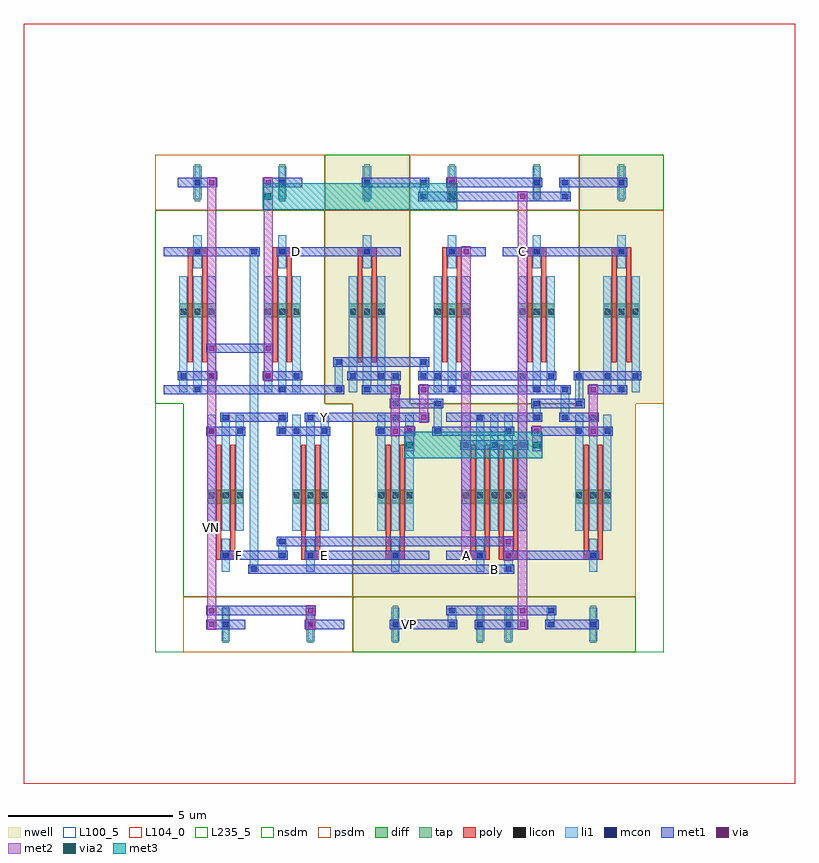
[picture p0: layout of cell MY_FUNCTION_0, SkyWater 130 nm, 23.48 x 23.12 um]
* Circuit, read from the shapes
.subckt MY_FUNCTION_0 A B C D E F VN VP Y
XM1 n1 B VN VN sky130_fd_pr__nfet_01v8 w=0.42 l=0.15 m=2
XM2 n2 F VN VN sky130_fd_pr__nfet_01v8 w=0.42 l=0.15 m=2
XM3 n1 D VN VN sky130_fd_pr__nfet_01v8 w=0.42 l=0.15 m=2
XM4 Y E n2 VN sky130_fd_pr__nfet_01v8 w=0.42 l=0.15 m=2
XM5 Y A n1 VN sky130_fd_pr__nfet_01v8 w=0.42 l=0.15 m=2
XM6 Y C n1 VN sky130_fd_pr__nfet_01v8 w=0.42 l=0.15 m=2
XM7 n3 D n4 VP sky130_fd_pr__pfet_01v8 w=0.42 l=0.15 m=2
XM8 Y E n3 VP sky130_fd_pr__pfet_01v8 w=0.42 l=0.15 m=2
XM9 n5 A VP VP sky130_fd_pr__pfet_01v8 w=0.42 l=0.15 m=2
XM10 n4 B VP VP sky130_fd_pr__pfet_01v8 w=0.42 l=0.15 m=2
XM11 Y F n3 VP sky130_fd_pr__pfet_01v8 w=0.42 l=0.15 m=2
XM12 n3 C n5 VP sky130_fd_pr__pfet_01v8 w=0.42 l=0.15 m=2
.ends

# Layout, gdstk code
from math import pi, radians
import gdstk
lib = gdstk.Library(unit=1e-6, precision=1e-09)
def R(c, l, rs):  # rectangles x0, y0, x1, y1
    for r in rs: c.add(gdstk.rectangle(r[:2], r[2:], *l))
def A(c, l, x, y, w, h, nx, ny, dx, dy):  # array of equal rectangles
    R(c, l, [(x+i*dx, y+j*dy, x+i*dx+w, y+j*dy+h) for i in range(nx) for j in range(ny)])
def P(c, l, *ps):  # polygons
    for p in ps: c.add(gdstk.Polygon(p, *l))
nwell = (64, 20)
diff = (65, 20)
tap = (65, 44)
poly = (66, 20)
licon = (66, 44)
li1 = (67, 20)
mcon = (67, 44)
met1 = (68, 20)
via = (68, 44)
met2 = (69, 20)
via2 = (69, 44)
met3 = (70, 20)
nsdm = (93, 44)
psdm = (94, 20)
L100_5 = (100, 5)
L104_0 = (104, 0)
L235_5 = (235, 5)

dp_pmos_47381084_x1_y1_1 = lib.new_cell('DP_PMOS_47381084_X1_Y1_1676456966')
R(dp_pmos_47381084_x1_y1_1, nwell, [(0,0,3.44,7.56)])
R(dp_pmos_47381084_x1_y1_1, diff, [(0.735,2.625,2.705,3.045)])
R(dp_pmos_47381084_x1_y1_1, tap, [(1.205,6.16,1.375,7.28), (2.065,6.16,2.235,7.28)])
A(dp_pmos_47381084_x1_y1_1, poly, 1, 1.26, 0.15, 3.36, 4, 1, 0.43, 0)
R(dp_pmos_47381084_x1_y1_1, poly, [(1,4.485,1.58,4.755), (1.86,4.485,2.44,4.755)])
A(dp_pmos_47381084_x1_y1_1, licon, 0.775, 2.705, 0.17, 0.17, 3, 1, 0.43, 0)
A(dp_pmos_47381084_x1_y1_1, licon, 1.635, 2.705, 0.17, 0.17, 3, 1, 0.43, 0)
R(dp_pmos_47381084_x1_y1_1, licon, [(1.205,4.535,1.375,4.705), (2.065,4.535,2.235,4.705), (1.205,6.635,1.375,6.805), (2.065,6.635,2.235,6.805)])
A(dp_pmos_47381084_x1_y1_1, li1, 0.735, 0.335, 0.25, 3.53, 5, 1, 0.43, 0)
R(dp_pmos_47381084_x1_y1_1, li1, [(1.165,4.115,1.415,5.125), (2.025,4.115,2.275,5.125), (1.165,6.215,1.415,7.225), (2.025,6.215,2.275,7.225)])
A(dp_pmos_47381084_x1_y1_1, mcon, 0.775, 1.175, 0.17, 0.17, 3, 1, 0.86, 0)
R(dp_pmos_47381084_x1_y1_1, mcon, [(1.205,0.335,1.375,0.505), (2.065,0.755,2.235,0.925), (1.205,4.535,1.375,4.705), (2.065,4.955,2.235,5.125), (1.205,6.635,1.375,6.805), (2.065,6.635,2.235,6.805)])
R(dp_pmos_47381084_x1_y1_1, met1, [(0.26,0.28,1.46,0.56), (1.12,0.7,2.32,0.98), (0.69,1.12,2.75,1.4), (0.26,4.48,1.46,4.76), (1.12,4.9,2.32,5.18), (1.12,6.58,2.75,6.86)])
R(dp_pmos_47381084_x1_y1_1, via, [(2.505,1.185,2.655,1.335), (2.505,6.645,2.655,6.795)])
R(dp_pmos_47381084_x1_y1_1, met2, [(2.44,1.1,2.72,6.88)])
R(dp_pmos_47381084_x1_y1_1, nsdm, [(0,5.88,3.44,7.56)])
R(dp_pmos_47381084_x1_y1_1, psdm, [(0,0,3.44,5.88)])
R(dp_pmos_47381084_x1_y1_1, L100_5, [(0,0,3.44,7.56)])

nmos_s_81537667_x1_y1_16 = lib.new_cell('NMOS_S_81537667_X1_Y1_1676456968')
R(nmos_s_81537667_x1_y1_16, diff, [(0.735,2.625,1.845,3.045)])
R(nmos_s_81537667_x1_y1_16, tap, [(1.205,6.16,1.375,7.28)])
R(nmos_s_81537667_x1_y1_16, poly, [(1,1.26,1.15,4.62), (1.43,1.26,1.58,4.62), (1,4.485,1.58,4.755)])
A(nmos_s_81537667_x1_y1_16, licon, 0.775, 2.705, 0.17, 0.17, 3, 1, 0.43, 0)
R(nmos_s_81537667_x1_y1_16, licon, [(1.205,4.535,1.375,4.705), (1.205,6.635,1.375,6.805)])
A(nmos_s_81537667_x1_y1_16, li1, 0.735, 0.335, 0.25, 3.53, 3, 1, 0.43, 0)
R(nmos_s_81537667_x1_y1_16, li1, [(1.165,4.115,1.415,5.125), (1.165,6.215,1.415,7.225)])
R(nmos_s_81537667_x1_y1_16, mcon, [(1.205,0.335,1.375,0.505), (0.775,0.755,0.945,0.925), (1.635,0.755,1.805,0.925), (1.205,4.535,1.375,4.705), (1.205,6.635,1.375,6.805)])
R(nmos_s_81537667_x1_y1_16, met1, [(0.26,0.28,1.46,0.56), (0.69,0.7,1.89,0.98), (0.26,4.48,1.46,4.76), (0.69,6.58,1.89,6.86)])
R(nmos_s_81537667_x1_y1_16, via, [(1.645,0.765,1.795,0.915), (1.645,6.645,1.795,6.795)])
R(nmos_s_81537667_x1_y1_16, met2, [(1.58,0.68,1.86,6.88)])
R(nmos_s_81537667_x1_y1_16, nsdm, [(0,0,2.58,5.88)])
R(nmos_s_81537667_x1_y1_16, psdm, [(0,5.88,2.58,7.56)])
R(nmos_s_81537667_x1_y1_16, L100_5, [(0,0,2.58,7.56)])

nmos_4t_58097119_x1_y1_1 = lib.new_cell('NMOS_4T_58097119_X1_Y1_1676456967')
R(nmos_4t_58097119_x1_y1_1, diff, [(0.735,2.625,1.845,3.045)])
R(nmos_4t_58097119_x1_y1_1, tap, [(1.205,6.16,1.375,7.28)])
R(nmos_4t_58097119_x1_y1_1, poly, [(1,1.26,1.15,4.62), (1.43,1.26,1.58,4.62), (1,4.485,1.58,4.755)])
A(nmos_4t_58097119_x1_y1_1, licon, 0.775, 2.705, 0.17, 0.17, 3, 1, 0.43, 0)
R(nmos_4t_58097119_x1_y1_1, licon, [(1.205,4.535,1.375,4.705), (1.205,6.635,1.375,6.805)])
A(nmos_4t_58097119_x1_y1_1, li1, 0.735, 0.335, 0.25, 3.53, 3, 1, 0.43, 0)
R(nmos_4t_58097119_x1_y1_1, li1, [(1.165,4.115,1.415,5.125), (1.165,6.215,1.415,7.225)])
R(nmos_4t_58097119_x1_y1_1, mcon, [(1.205,0.335,1.375,0.505), (0.775,0.755,0.945,0.925), (1.635,0.755,1.805,0.925), (1.205,4.535,1.375,4.705), (1.205,6.635,1.375,6.805)])
R(nmos_4t_58097119_x1_y1_1, met1, [(0.26,0.28,1.46,0.56), (0.69,0.7,1.89,0.98), (0.26,4.48,1.46,4.76), (0.26,6.58,1.46,6.86)])
R(nmos_4t_58097119_x1_y1_1, nsdm, [(0,0,2.58,5.88)])
R(nmos_4t_58097119_x1_y1_1, psdm, [(0,5.88,2.58,7.56)])
R(nmos_4t_58097119_x1_y1_1, L100_5, [(0,0,2.58,7.56)])

pmos_4t_68898473_x1_y1_1 = lib.new_cell('PMOS_4T_68898473_X1_Y1_1676456969')
R(pmos_4t_68898473_x1_y1_1, nwell, [(0,0,2.58,7.56)])
R(pmos_4t_68898473_x1_y1_1, diff, [(0.735,2.625,1.845,3.045)])
R(pmos_4t_68898473_x1_y1_1, tap, [(1.205,6.16,1.375,7.28)])
R(pmos_4t_68898473_x1_y1_1, poly, [(1,1.26,1.15,4.62), (1.43,1.26,1.58,4.62), (1,4.485,1.58,4.755)])
A(pmos_4t_68898473_x1_y1_1, licon, 0.775, 2.705, 0.17, 0.17, 3, 1, 0.43, 0)
R(pmos_4t_68898473_x1_y1_1, licon, [(1.205,4.535,1.375,4.705), (1.205,6.635,1.375,6.805)])
A(pmos_4t_68898473_x1_y1_1, li1, 0.735, 0.335, 0.25, 3.53, 3, 1, 0.43, 0)
R(pmos_4t_68898473_x1_y1_1, li1, [(1.165,4.115,1.415,5.125), (1.165,6.215,1.415,7.225)])
R(pmos_4t_68898473_x1_y1_1, mcon, [(1.205,0.335,1.375,0.505), (0.775,0.755,0.945,0.925), (1.635,0.755,1.805,0.925), (1.205,4.535,1.375,4.705), (1.205,6.635,1.375,6.805)])
R(pmos_4t_68898473_x1_y1_1, met1, [(0.26,0.28,1.46,0.56), (0.69,0.7,1.89,0.98), (0.26,4.48,1.46,4.76), (0.26,6.58,1.46,6.86)])
R(pmos_4t_68898473_x1_y1_1, nsdm, [(0,5.88,2.58,7.56)])
R(pmos_4t_68898473_x1_y1_1, psdm, [(0,0,2.58,5.88)])
R(pmos_4t_68898473_x1_y1_1, L100_5, [(0,0,2.58,7.56)])

my_function_0 = lib.new_cell('MY_FUNCTION_0')
R(my_function_0, li1, [(8.905,0.755,9.155,0.925), (8.905,0.755,9.155,0.925), (8.905,0.755,9.155,0.925), (8.905,0.755,9.155,0.925), (8.905,0.755,9.155,0.925), (8.905,0.755,9.155,0.925), (8.905,0.755,9.155,0.925), (8.905,0.755,9.155,0.925), (11.915,0.755,12.165,0.925), (11.915,0.755,12.165,0.925), (11.915,0.755,12.165,0.925), (11.915,0.755,12.165,0.925), (11.915,0.755,12.165,0.925), (11.915,0.755,12.165,0.925), (11.915,0.755,12.165,0.925), (11.915,0.755,12.165,0.925), (8.905,0.84,9.155,1.26), (11.915,0.84,12.165,1.26), (8.905,1.175,9.155,1.345), (8.905,1.175,9.155,1.345), (8.905,1.175,9.155,1.345), (8.905,1.175,9.155,1.345), (8.905,1.175,9.155,1.345), (8.905,1.175,9.155,1.345), (8.905,1.175,9.155,1.345), (8.905,1.175,9.155,1.345), (11.915,1.175,12.165,1.345), (11.915,1.175,12.165,1.345), (11.915,1.175,12.165,1.345), (11.915,1.175,12.165,1.345), (11.915,1.175,12.165,1.345), (11.915,1.175,12.165,1.345), (11.915,1.175,12.165,1.345), (11.915,1.175,12.165,1.345), (2.885,2.435,3.135,2.605), (2.885,2.435,3.135,2.605), (2.885,2.52,3.135,12.18), (3.745,2.855,3.995,3.025), (3.745,2.855,3.995,3.025), (3.745,2.94,3.995,3.36), (3.745,3.275,3.995,3.445), (3.745,3.275,3.995,3.445), (3.745,6.635,3.995,6.805), (3.745,6.635,3.995,6.805), (8.475,6.635,8.725,6.805), (8.475,6.635,8.725,6.805), (3.745,6.72,3.995,7.14), (8.475,6.72,8.725,7.56), (3.745,7.055,3.995,7.225), (3.745,7.055,3.995,7.225), (11.485,7.055,11.735,7.225), (11.485,7.055,11.735,7.225), (12.345,7.055,12.595,7.225), (12.345,7.055,12.595,7.225), (11.485,7.14,11.735,7.56), (12.345,7.14,12.595,7.98), (7.185,7.475,7.435,7.645), (7.185,7.475,7.435,7.645), (8.475,7.475,8.725,7.645), (8.475,7.475,8.725,7.645), (11.485,7.475,11.735,7.645), (11.485,7.475,11.735,7.645), (12.775,7.475,13.025,7.645), (12.775,7.475,13.025,7.645), (7.185,7.56,7.435,8.4), (12.775,7.56,13.025,8.4), (5.465,7.895,5.715,8.065), (5.465,7.895,5.715,8.065), (5.465,7.895,5.715,8.065), (5.465,7.895,5.715,8.065), (12.345,7.895,12.595,8.065), (12.345,7.895,12.595,8.065), (5.465,7.98,5.715,8.82), (7.185,8.315,7.435,8.485), (7.185,8.315,7.435,8.485), (8.045,8.315,8.295,8.485), (8.045,8.315,8.295,8.485), (8.045,8.315,8.295,8.485), (8.045,8.315,8.295,8.485), (12.775,8.315,13.025,8.485), (12.775,8.315,13.025,8.485), (8.045,8.4,8.295,8.82), (5.465,8.735,5.715,8.905), (5.465,8.735,5.715,8.905), (5.465,8.735,5.715,8.905), (5.465,8.735,5.715,8.905), (8.045,8.735,8.295,8.905), (8.045,8.735,8.295,8.905), (8.045,8.735,8.295,8.905), (8.045,8.735,8.295,8.905), (2.885,12.095,3.135,12.265), (2.885,12.095,3.135,12.265), (8.045,13.775,8.295,13.945), (8.045,13.775,8.295,13.945), (12.345,13.775,12.595,13.945), (12.345,13.775,12.595,13.945), (12.345,13.775,12.595,13.945), (12.345,13.775,12.595,13.945), (8.045,13.86,8.295,14.28), (12.345,13.86,12.595,14.28), (8.045,14.195,8.295,14.365), (8.045,14.195,8.295,14.365), (12.345,14.195,12.595,14.365), (12.345,14.195,12.595,14.365), (12.345,14.195,12.595,14.365), (12.345,14.195,12.595,14.365)])
R(my_function_0, mcon, [(8.945,0.755,9.115,0.925), (8.945,0.755,9.115,0.925), (8.945,0.755,9.115,0.925), (8.945,0.755,9.115,0.925), (8.945,0.755,9.115,0.925), (8.945,0.755,9.115,0.925), (8.945,0.755,9.115,0.925), (8.945,0.755,9.115,0.925), (11.955,0.755,12.125,0.925), (11.955,0.755,12.125,0.925), (11.955,0.755,12.125,0.925), (11.955,0.755,12.125,0.925), (11.955,0.755,12.125,0.925), (11.955,0.755,12.125,0.925), (11.955,0.755,12.125,0.925), (11.955,0.755,12.125,0.925), (8.945,1.175,9.115,1.345), (8.945,1.175,9.115,1.345), (8.945,1.175,9.115,1.345), (8.945,1.175,9.115,1.345), (8.945,1.175,9.115,1.345), (8.945,1.175,9.115,1.345), (8.945,1.175,9.115,1.345), (8.945,1.175,9.115,1.345), (11.955,1.175,12.125,1.345), (11.955,1.175,12.125,1.345), (11.955,1.175,12.125,1.345), (11.955,1.175,12.125,1.345), (11.955,1.175,12.125,1.345), (11.955,1.175,12.125,1.345), (11.955,1.175,12.125,1.345), (11.955,1.175,12.125,1.345), (2.925,2.435,3.095,2.605), (2.925,2.435,3.095,2.605), (3.785,2.855,3.955,3.025), (3.785,2.855,3.955,3.025), (3.785,3.275,3.955,3.445), (3.785,3.275,3.955,3.445), (3.785,6.635,3.955,6.805), (3.785,6.635,3.955,6.805), (8.515,6.635,8.685,6.805), (8.515,6.635,8.685,6.805), (3.785,7.055,3.955,7.225), (3.785,7.055,3.955,7.225), (11.525,7.055,11.695,7.225), (11.525,7.055,11.695,7.225), (12.385,7.055,12.555,7.225), (12.385,7.055,12.555,7.225), (7.225,7.475,7.395,7.645), (7.225,7.475,7.395,7.645), (8.515,7.475,8.685,7.645), (8.515,7.475,8.685,7.645), (11.525,7.475,11.695,7.645), (11.525,7.475,11.695,7.645), (12.815,7.475,12.985,7.645), (12.815,7.475,12.985,7.645), (5.505,7.895,5.675,8.065), (5.505,7.895,5.675,8.065), (5.505,7.895,5.675,8.065), (5.505,7.895,5.675,8.065), (12.385,7.895,12.555,8.065), (12.385,7.895,12.555,8.065), (7.225,8.315,7.395,8.485), (7.225,8.315,7.395,8.485), (8.085,8.315,8.255,8.485), (8.085,8.315,8.255,8.485), (8.085,8.315,8.255,8.485), (8.085,8.315,8.255,8.485), (12.815,8.315,12.985,8.485), (12.815,8.315,12.985,8.485), (5.505,8.735,5.675,8.905), (5.505,8.735,5.675,8.905), (5.505,8.735,5.675,8.905), (5.505,8.735,5.675,8.905), (8.085,8.735,8.255,8.905), (8.085,8.735,8.255,8.905), (8.085,8.735,8.255,8.905), (8.085,8.735,8.255,8.905), (2.925,12.095,3.095,12.265), (2.925,12.095,3.095,12.265), (8.085,13.775,8.255,13.945), (8.085,13.775,8.255,13.945), (12.385,13.775,12.555,13.945), (12.385,13.775,12.555,13.945), (12.385,13.775,12.555,13.945), (12.385,13.775,12.555,13.945), (8.085,14.195,8.255,14.365), (8.085,14.195,8.255,14.365), (12.385,14.195,12.555,14.365), (12.385,14.195,12.555,14.365), (12.385,14.195,12.555,14.365), (12.385,14.195,12.555,14.365)])
A(my_function_0, met1, 8.17, 7.84, 0.86, 0.28, 3, 1, 1.72, 0)
A(my_function_0, met1, 7.31, 14.14, 0.86, 0.28, 3, 1, 2.58, 0)
R(my_function_0, met1, [(4.57,0.7,4.89,0.98), (4.57,0.7,4.89,0.98), (4.57,0.7,4.89,0.98), (4.57,0.7,4.89,0.98), (4.57,0.7,4.89,0.98), (4.57,0.7,4.89,0.98), (4.57,0.7,4.89,0.98), (4.57,0.7,4.89,0.98), (4.57,0.7,4.89,0.98), (4.57,0.7,4.89,0.98), (8.17,0.7,9.03,0.98), (8.86,0.7,9.2,0.98), (8.86,0.7,9.2,0.98), (8.86,0.7,9.2,0.98), (8.86,0.7,9.2,0.98), (8.86,0.7,9.2,0.98), (8.86,0.7,9.2,0.98), (8.86,0.7,9.2,0.98), (8.86,0.7,9.2,0.98), (11.87,0.7,12.21,0.98), (11.87,0.7,12.21,0.98), (11.87,0.7,12.21,0.98), (11.87,0.7,12.21,0.98), (11.87,0.7,12.21,0.98), (11.87,0.7,12.21,0.98), (11.87,0.7,12.21,0.98), (11.87,0.7,12.21,0.98), (12.04,0.7,12.47,0.98), (1.56,1.12,1.88,1.4), (1.56,1.12,1.88,1.4), (1.56,1.12,1.88,1.4), (1.56,1.12,1.88,1.4), (1.56,1.12,1.88,1.4), (1.56,1.12,1.88,1.4), (1.56,1.12,1.88,1.4), (1.56,1.12,1.88,1.4), (1.56,1.12,1.88,1.4), (1.56,1.12,1.88,1.4), (1.72,1.12,4.73,1.4), (4.57,1.12,4.89,1.4), (4.57,1.12,4.89,1.4), (4.57,1.12,4.89,1.4), (4.57,1.12,4.89,1.4), (4.57,1.12,4.89,1.4), (4.57,1.12,4.89,1.4), (4.57,1.12,4.89,1.4), (4.57,1.12,4.89,1.4), (4.57,1.12,4.89,1.4), (4.57,1.12,4.89,1.4), (8.86,1.12,9.2,1.4), (8.86,1.12,9.2,1.4), (8.86,1.12,9.2,1.4), (8.86,1.12,9.2,1.4), (8.86,1.12,9.2,1.4), (8.86,1.12,9.2,1.4), (8.86,1.12,9.2,1.4), (8.86,1.12,9.2,1.4), (9.03,1.12,12.04,1.4), (11.02,1.12,11.34,1.4), (11.02,1.12,11.34,1.4), (11.02,1.12,11.34,1.4), (11.02,1.12,11.34,1.4), (11.02,1.12,11.34,1.4), (11.02,1.12,11.34,1.4), (11.87,1.12,12.21,1.4), (11.87,1.12,12.21,1.4), (11.87,1.12,12.21,1.4), (11.87,1.12,12.21,1.4), (11.87,1.12,12.21,1.4), (11.87,1.12,12.21,1.4), (11.87,1.12,12.21,1.4), (11.87,1.12,12.21,1.4), (2.84,2.38,3.18,2.66), (2.84,2.38,3.18,2.66), (3.01,2.38,9.89,2.66), (3.01,2.8,3.87,3.08), (3.7,2.8,4.04,3.08), (3.7,2.8,4.04,3.08), (5.59,2.8,7.31,3.08), (9.3,2.8,9.62,3.08), (9.3,2.8,9.62,3.08), (10.59,2.8,10.91,3.08), (10.59,2.8,10.91,3.08), (10.75,2.8,12.47,3.08), (3.7,3.22,4.04,3.5), (3.7,3.22,4.04,3.5), (3.87,3.22,10.75,3.5), (10.59,3.22,10.91,3.5), (10.59,3.22,10.91,3.5), (3.7,6.58,4.04,6.86), (3.7,6.58,4.04,6.86), (3.87,6.58,4.3,6.86), (7.15,6.58,7.47,6.86), (7.15,6.58,7.47,6.86), (7.15,6.58,7.47,6.86), (7.15,6.58,7.47,6.86), (7.15,6.58,7.47,6.86), (7.15,6.58,7.47,6.86), (7.58,6.58,7.9,6.86), (7.58,6.58,7.9,6.86), (7.58,6.58,7.9,6.86), (7.58,6.58,7.9,6.86), (8.43,6.58,8.77,6.86), (8.43,6.58,8.77,6.86), (8.6,6.58,9.89,6.86), (11.45,6.58,11.77,6.86), (11.45,6.58,11.77,6.86), (11.45,6.58,11.77,6.86), (11.45,6.58,11.77,6.86), (11.61,6.58,12.9,6.86), (13.17,6.58,13.49,6.86), (13.17,6.58,13.49,6.86), (3.01,7,3.87,7.28), (3.7,7,4.04,7.28), (3.7,7,4.04,7.28), (5.59,7,7.31,7.28), (8.01,7,8.33,7.28), (8.01,7,8.33,7.28), (8.01,7,8.33,7.28), (8.01,7,8.33,7.28), (8.01,7,8.33,7.28), (8.01,7,8.33,7.28), (9.89,7,11.61,7.28), (11.44,7,11.78,7.28), (11.44,7,11.78,7.28), (12.3,7,12.64,7.28), (12.3,7,12.64,7.28), (7.14,7.42,7.48,7.7), (7.14,7.42,7.48,7.7), (7.31,7.42,8.6,7.7), (8.43,7.42,8.77,7.7), (8.43,7.42,8.77,7.7), (11.44,7.42,11.78,7.7), (11.44,7.42,11.78,7.7), (11.61,7.42,12.9,7.7), (12.73,7.42,13.07,7.7), (12.73,7.42,13.07,7.7), (1.29,7.84,3.87,8.12), (4.73,7.84,5.59,8.12), (5.42,7.84,5.76,8.12), (5.42,7.84,5.76,8.12), (5.42,7.84,5.76,8.12), (5.42,7.84,5.76,8.12), (7.15,7.84,7.47,8.12), (7.15,7.84,7.47,8.12), (7.15,7.84,7.47,8.12), (7.15,7.84,7.47,8.12), (7.15,7.84,7.47,8.12), (7.15,7.84,7.47,8.12), (8.01,7.84,8.33,8.12), (8.01,7.84,8.33,8.12), (8.01,7.84,8.33,8.12), (8.01,7.84,8.33,8.12), (8.01,7.84,8.33,8.12), (8.01,7.84,8.33,8.12), (12.3,7.84,12.64,8.12), (12.3,7.84,12.64,8.12), (13.17,7.84,13.49,8.12), (13.17,7.84,13.49,8.12), (6.88,8.26,7.31,8.54), (7.14,8.26,7.48,8.54), (7.14,8.26,7.48,8.54), (8,8.26,8.34,8.54), (8,8.26,8.34,8.54), (8,8.26,8.34,8.54), (8,8.26,8.34,8.54), (8.17,8.26,8.6,8.54), (9.46,8.26,11.18,8.54), (12.73,8.26,13.07,8.54), (12.73,8.26,13.07,8.54), (12.9,8.26,13.76,8.54), (5.42,8.68,5.76,8.96), (5.42,8.68,5.76,8.96), (5.42,8.68,5.76,8.96), (5.42,8.68,5.76,8.96), (5.59,8.68,8.17,8.96), (8,8.68,8.34,8.96), (8,8.68,8.34,8.96), (8,8.68,8.34,8.96), (8,8.68,8.34,8.96), (1.56,9.1,1.88,9.38), (1.56,9.1,1.88,9.38), (1.56,9.1,1.88,9.38), (1.56,9.1,1.88,9.38), (1.56,9.1,1.88,9.38), (1.56,9.1,1.88,9.38), (1.72,9.1,3.44,9.38), (3.28,9.1,3.6,9.38), (3.28,9.1,3.6,9.38), (3.28,9.1,3.6,9.38), (3.28,9.1,3.6,9.38), (3.28,9.1,3.6,9.38), (3.28,9.1,3.6,9.38), (1.29,12.04,3.01,12.32), (2.84,12.04,3.18,12.32), (2.84,12.04,3.18,12.32), (4.73,12.04,6.45,12.32), (9.3,12.04,9.62,12.32), (9.3,12.04,9.62,12.32), (11.61,12.04,13.33,12.32), (8,13.72,8.34,14), (8,13.72,8.34,14), (8.17,13.72,11.18,14), (11.02,13.72,11.34,14), (11.02,13.72,11.34,14), (11.02,13.72,11.34,14), (11.02,13.72,11.34,14), (11.18,13.72,12.47,14), (12.3,13.72,12.64,14), (12.3,13.72,12.64,14), (12.3,13.72,12.64,14), (12.3,13.72,12.64,14), (8,14.14,8.34,14.42), (8,14.14,8.34,14.42), (8.87,14.14,9.19,14.42), (8.87,14.14,9.19,14.42), (8.87,14.14,9.19,14.42), (8.87,14.14,9.19,14.42), (12.3,14.14,12.64,14.42), (12.3,14.14,12.64,14.42), (12.3,14.14,12.64,14.42), (12.3,14.14,12.64,14.42)])
P(my_function_0, met1, [(0,0),(0,0),(0,0),(0,0)],
  [(0,0),(0,0),(0,0),(0,0)],
  [(0,0),(0,0),(0,0),(0,0)],
  [(0,0),(0,0),(0,0),(0,0)],
  [(0,0),(0,0),(0,0),(0,0)],
  [(0,0),(0,0),(0,0),(0,0)],
  [(0,0),(0,0),(0,0),(0,0)],
  [(0,0),(0,0),(0,0),(0,0)],
  [(0,0),(0,0),(0,0),(0,0)],
  [(0,0),(0,0),(0,0),(0,0)],
  [(0,0),(0,0),(0,0),(0,0)],
  [(0,0),(0,0),(0,0),(0,0)],
  [(0,0),(0,0),(0,0),(0,0)],
  [(0,0),(0,0),(0,0),(0,0)],
  [(0,0),(0,0),(0,0),(0,0)],
  [(0,0),(0,0),(0,0),(0,0)],
  [(0,0),(0,0),(0,0),(0,0)],
  [(0,0),(0,0),(0,0),(0,0)],
  [(0,0),(0,0),(0,0),(0,0)],
  [(0,0),(0,0),(0,0),(0,0)],
  [(0,0),(0,0),(0,0),(0,0)],
  [(0,0),(0,0),(0,0),(0,0)],
  [(0,0),(0,0),(0,0),(0,0)],
  [(0,0),(0,0),(0,0),(0,0)],
  [(0,0),(0,0),(0,0),(0,0)],
  [(0,0),(0,0),(0,0),(0,0)],
  [(0,0),(0,0),(0,0),(0,0)],
  [(0,0),(0,0),(0,0),(0,0)],
  [(0,0),(0,0),(0,0),(0,0)],
  [(0,0),(0,0),(0,0),(0,0)],
  [(0,0),(0,0),(0,0),(0,0)],
  [(0,0),(0,0),(0,0),(0,0)],
  [(0,0),(0,0),(0,0),(0,0)],
  [(0,0),(0,0),(0,0),(0,0)],
  [(0,0),(0,0),(0,0),(0,0)],
  [(0,0),(0,0),(0,0),(0,0)],
  [(0,0),(0,0),(0,0),(0,0)],
  [(0,0),(0,0),(0,0),(0,0)],
  [(0,0),(0,0),(0,0),(0,0)],
  [(0,0),(0,0),(0,0),(0,0)],
  [(0,0),(0,0),(0,0),(0,0)],
  [(0,0),(0,0),(0,0),(0,0)],
  [(0,0),(0,0),(0,0),(0,0)],
  [(0,0),(0,0),(0,0),(0,0)],
  [(0,0),(0,0),(0,0),(0,0)],
  [(0,0),(0,0),(0,0),(0,0)])
R(my_function_0, via, [(4.655,0.765,4.805,0.915), (4.655,0.765,4.805,0.915), (4.655,0.765,4.805,0.915), (4.655,0.765,4.805,0.915), (4.655,0.765,4.805,0.915), (4.655,0.765,4.805,0.915), (4.655,0.765,4.805,0.915), (4.655,0.765,4.805,0.915), (4.655,0.765,4.805,0.915), (4.655,0.765,4.805,0.915), (1.645,1.185,1.795,1.335), (1.645,1.185,1.795,1.335), (1.645,1.185,1.795,1.335), (1.645,1.185,1.795,1.335), (1.645,1.185,1.795,1.335), (1.645,1.185,1.795,1.335), (1.645,1.185,1.795,1.335), (1.645,1.185,1.795,1.335), (1.645,1.185,1.795,1.335), (1.645,1.185,1.795,1.335), (4.655,1.185,4.805,1.335), (4.655,1.185,4.805,1.335), (4.655,1.185,4.805,1.335), (4.655,1.185,4.805,1.335), (4.655,1.185,4.805,1.335), (4.655,1.185,4.805,1.335), (4.655,1.185,4.805,1.335), (4.655,1.185,4.805,1.335), (4.655,1.185,4.805,1.335), (4.655,1.185,4.805,1.335), (11.105,1.185,11.255,1.335), (11.105,1.185,11.255,1.335), (11.105,1.185,11.255,1.335), (11.105,1.185,11.255,1.335), (11.105,1.185,11.255,1.335), (11.105,1.185,11.255,1.335), (9.385,2.865,9.535,3.015), (9.385,2.865,9.535,3.015), (10.675,2.865,10.825,3.015), (10.675,2.865,10.825,3.015), (10.675,3.285,10.825,3.435), (10.675,3.285,10.825,3.435), (7.235,6.645,7.385,6.795), (7.235,6.645,7.385,6.795), (7.235,6.645,7.385,6.795), (7.235,6.645,7.385,6.795), (7.235,6.645,7.385,6.795), (7.235,6.645,7.385,6.795), (7.665,6.645,7.815,6.795), (7.665,6.645,7.815,6.795), (7.665,6.645,7.815,6.795), (7.665,6.645,7.815,6.795), (11.535,6.645,11.685,6.795), (11.535,6.645,11.685,6.795), (11.535,6.645,11.685,6.795), (11.535,6.645,11.685,6.795), (13.255,6.645,13.405,6.795), (13.255,6.645,13.405,6.795), (8.095,7.065,8.245,7.215), (8.095,7.065,8.245,7.215), (8.095,7.065,8.245,7.215), (8.095,7.065,8.245,7.215), (8.095,7.065,8.245,7.215), (8.095,7.065,8.245,7.215), (7.235,7.905,7.385,8.055), (7.235,7.905,7.385,8.055), (7.235,7.905,7.385,8.055), (7.235,7.905,7.385,8.055), (7.235,7.905,7.385,8.055), (7.235,7.905,7.385,8.055), (8.095,7.905,8.245,8.055), (8.095,7.905,8.245,8.055), (8.095,7.905,8.245,8.055), (8.095,7.905,8.245,8.055), (8.095,7.905,8.245,8.055), (8.095,7.905,8.245,8.055), (13.255,7.905,13.405,8.055), (13.255,7.905,13.405,8.055), (1.645,9.165,1.795,9.315), (1.645,9.165,1.795,9.315), (1.645,9.165,1.795,9.315), (1.645,9.165,1.795,9.315), (1.645,9.165,1.795,9.315), (1.645,9.165,1.795,9.315), (3.365,9.165,3.515,9.315), (3.365,9.165,3.515,9.315), (3.365,9.165,3.515,9.315), (3.365,9.165,3.515,9.315), (3.365,9.165,3.515,9.315), (3.365,9.165,3.515,9.315), (9.385,12.105,9.535,12.255), (9.385,12.105,9.535,12.255), (11.105,13.785,11.255,13.935), (11.105,13.785,11.255,13.935), (11.105,13.785,11.255,13.935), (11.105,13.785,11.255,13.935), (8.955,14.205,9.105,14.355), (8.955,14.205,9.105,14.355), (8.955,14.205,9.105,14.355), (8.955,14.205,9.105,14.355)])
R(my_function_0, met2, [(4.59,0.68,4.87,1), (4.59,0.68,4.87,1), (4.59,0.68,4.87,1), (4.59,0.68,4.87,1), (4.59,0.68,4.87,1), (4.59,0.68,4.87,1), (4.59,0.68,4.87,1), (4.59,0.68,4.87,1), (4.59,0.68,4.87,1), (4.59,0.68,4.87,1), (4.59,0.84,4.87,1.26), (1.58,1.1,1.86,1.42), (1.58,1.1,1.86,1.42), (1.58,1.1,1.86,1.42), (1.58,1.1,1.86,1.42), (1.58,1.1,1.86,1.42), (1.58,1.1,1.86,1.42), (1.58,1.1,1.86,1.42), (1.58,1.1,1.86,1.42), (1.58,1.1,1.86,1.42), (1.58,1.1,1.86,1.42), (4.59,1.1,4.87,1.42), (4.59,1.1,4.87,1.42), (4.59,1.1,4.87,1.42), (4.59,1.1,4.87,1.42), (4.59,1.1,4.87,1.42), (4.59,1.1,4.87,1.42), (4.59,1.1,4.87,1.42), (4.59,1.1,4.87,1.42), (4.59,1.1,4.87,1.42), (4.59,1.1,4.87,1.42), (11.04,1.1,11.32,1.42), (11.04,1.1,11.32,1.42), (11.04,1.1,11.32,1.42), (11.04,1.1,11.32,1.42), (11.04,1.1,11.32,1.42), (11.04,1.1,11.32,1.42), (9.32,2.78,9.6,3.1), (9.32,2.78,9.6,3.1), (10.61,2.78,10.89,3.1), (10.61,2.78,10.89,3.1), (9.32,2.94,9.6,12.18), (10.61,2.94,10.89,3.36), (10.61,3.2,10.89,3.52), (10.61,3.2,10.89,3.52), (7.6,6.115,7.88,6.485), (7.6,6.115,7.88,6.485), (7.6,6.115,7.88,6.485), (7.6,6.115,7.88,6.485), (11.47,6.115,11.75,6.485), (11.47,6.115,11.75,6.485), (11.47,6.115,11.75,6.485), (11.47,6.115,11.75,6.485), (7.6,6.3,7.88,6.72), (11.04,6.3,11.32,13.86), (11.47,6.3,11.75,6.72), (7.17,6.56,7.45,6.88), (7.17,6.56,7.45,6.88), (7.17,6.56,7.45,6.88), (7.17,6.56,7.45,6.88), (7.17,6.56,7.45,6.88), (7.17,6.56,7.45,6.88), (7.6,6.56,7.88,6.88), (7.6,6.56,7.88,6.88), (7.6,6.56,7.88,6.88), (7.6,6.56,7.88,6.88), (11.47,6.56,11.75,6.88), (11.47,6.56,11.75,6.88), (11.47,6.56,11.75,6.88), (11.47,6.56,11.75,6.88), (13.19,6.56,13.47,6.88), (13.19,6.56,13.47,6.88), (1.58,6.72,1.86,8.4), (7.17,6.72,7.45,7.98), (13.19,6.72,13.47,7.98), (8.03,6.98,8.31,7.3), (8.03,6.98,8.31,7.3), (8.03,6.98,8.31,7.3), (8.03,6.98,8.31,7.3), (8.03,6.98,8.31,7.3), (8.03,6.98,8.31,7.3), (8.03,7.14,8.31,7.98), (7.17,7.82,7.45,8.14), (7.17,7.82,7.45,8.14), (7.17,7.82,7.45,8.14), (7.17,7.82,7.45,8.14), (7.17,7.82,7.45,8.14), (7.17,7.82,7.45,8.14), (8.03,7.82,8.31,8.14), (8.03,7.82,8.31,8.14), (8.03,7.82,8.31,8.14), (8.03,7.82,8.31,8.14), (8.03,7.82,8.31,8.14), (8.03,7.82,8.31,8.14), (13.19,7.82,13.47,8.14), (13.19,7.82,13.47,8.14), (1.58,9.08,1.86,9.4), (1.58,9.08,1.86,9.4), (1.58,9.08,1.86,9.4), (1.58,9.08,1.86,9.4), (1.58,9.08,1.86,9.4), (1.58,9.08,1.86,9.4), (3.3,9.08,3.58,9.4), (3.3,9.08,3.58,9.4), (3.3,9.08,3.58,9.4), (3.3,9.08,3.58,9.4), (3.3,9.08,3.58,9.4), (3.3,9.08,3.58,9.4), (9.32,12.02,9.6,12.34), (9.32,12.02,9.6,12.34), (3.3,13.675,3.58,14.045), (3.3,13.675,3.58,14.045), (3.3,13.675,3.58,14.045), (3.3,13.675,3.58,14.045), (8.89,13.675,9.17,14.045), (8.89,13.675,9.17,14.045), (8.89,13.675,9.17,14.045), (8.89,13.675,9.17,14.045), (11.04,13.7,11.32,14.02), (11.04,13.7,11.32,14.02), (11.04,13.7,11.32,14.02), (11.04,13.7,11.32,14.02), (8.89,13.86,9.17,14.28), (8.89,14.12,9.17,14.44), (8.89,14.12,9.17,14.44), (8.89,14.12,9.17,14.44), (8.89,14.12,9.17,14.44)])
P(my_function_0, met2, [(0,0),(0,0),(0,0),(0,0)],
  [(0,0),(0,0),(0,0),(0,0)],
  [(0,0),(0,0),(0,0),(0,0)],
  [(0,0),(0,0),(0,0),(0,0)],
  [(0,0),(0,0),(0,0),(0,0)])
R(my_function_0, via2, [(7.64,6.2,7.84,6.4), (7.64,6.2,7.84,6.4), (7.64,6.2,7.84,6.4), (7.64,6.2,7.84,6.4), (11.51,6.2,11.71,6.4), (11.51,6.2,11.71,6.4), (11.51,6.2,11.71,6.4), (11.51,6.2,11.71,6.4), (3.34,13.76,3.54,13.96), (3.34,13.76,3.54,13.96), (3.34,13.76,3.54,13.96), (3.34,13.76,3.54,13.96), (8.93,13.76,9.13,13.96), (8.93,13.76,9.13,13.96), (8.93,13.76,9.13,13.96), (8.93,13.76,9.13,13.96)])
R(my_function_0, met3, [(7.575,5.9,7.905,6.7), (7.575,5.9,7.905,6.7), (7.575,5.9,7.905,6.7), (7.575,5.9,7.905,6.7), (7.74,5.9,11.61,6.7), (11.445,5.9,11.775,6.7), (11.445,5.9,11.775,6.7), (11.445,5.9,11.775,6.7), (11.445,5.9,11.775,6.7), (3.275,13.46,3.605,14.26), (3.275,13.46,3.605,14.26), (3.275,13.46,3.605,14.26), (3.275,13.46,3.605,14.26), (3.44,13.46,9.03,14.26), (8.865,13.46,9.195,14.26), (8.865,13.46,9.195,14.26), (8.865,13.46,9.195,14.26), (8.865,13.46,9.195,14.26)])
R(my_function_0, L104_0, [(-4,-4,19.48,19.12)])
R(my_function_0, L235_5, [(0,0,15.48,15.12)])
my_function_0.add(gdstk.Reference(dp_pmos_47381084_x1_y1_1, (8.6,7.56), x_reflection=True))
my_function_0.add(gdstk.Reference(nmos_s_81537667_x1_y1_16, (0,7.56)))
my_function_0.add(gdstk.Reference(nmos_s_81537667_x1_y1_16, (5.16,7.56), rotation=pi, x_reflection=True))
my_function_0.add(gdstk.Reference(nmos_s_81537667_x1_y1_16, (3.44,7.56), rotation=pi))
my_function_0.add(gdstk.Reference(nmos_4t_58097119_x1_y1_1, (10.32,7.56), rotation=pi, x_reflection=True))
my_function_0.add(gdstk.Reference(nmos_4t_58097119_x1_y1_1, (10.32,7.56)))
my_function_0.add(gdstk.Reference(nmos_4t_58097119_x1_y1_1, (6.02,7.56), rotation=pi))
my_function_0.add(gdstk.Reference(pmos_4t_68898473_x1_y1_1, (8.6,7.56), rotation=pi))
my_function_0.add(gdstk.Reference(pmos_4t_68898473_x1_y1_1, (12.04,7.56), x_reflection=True))
my_function_0.add(gdstk.Reference(pmos_4t_68898473_x1_y1_1, (12.9,7.56)))
my_function_0.add(gdstk.Reference(pmos_4t_68898473_x1_y1_1, (7.74,7.56), rotation=pi, x_reflection=True))
my_function_0.add(gdstk.Label('A', (9.46,2.94), layer=68, texttype=5))
my_function_0.add(gdstk.Label('B', (10.32,2.52), layer=68, texttype=5))
my_function_0.add(gdstk.Label('VP', (7.74,0.84), layer=68, texttype=5))
my_function_0.add(gdstk.Label('VN', (1.72,3.78), layer=69, texttype=5))
my_function_0.add(gdstk.Label('D', (4.3,12.18), layer=68, texttype=5))
my_function_0.add(gdstk.Label('F', (2.58,2.94), layer=68, texttype=5))
my_function_0.add(gdstk.Label('Y', (5.16,7.14), layer=68, texttype=5))
my_function_0.add(gdstk.Label('C', (11.18,12.18), layer=68, texttype=5))
my_function_0.add(gdstk.Label('E', (5.16,2.94), layer=68, texttype=5))

lib.write_gds('MY_FUNCTION_0.gds')
